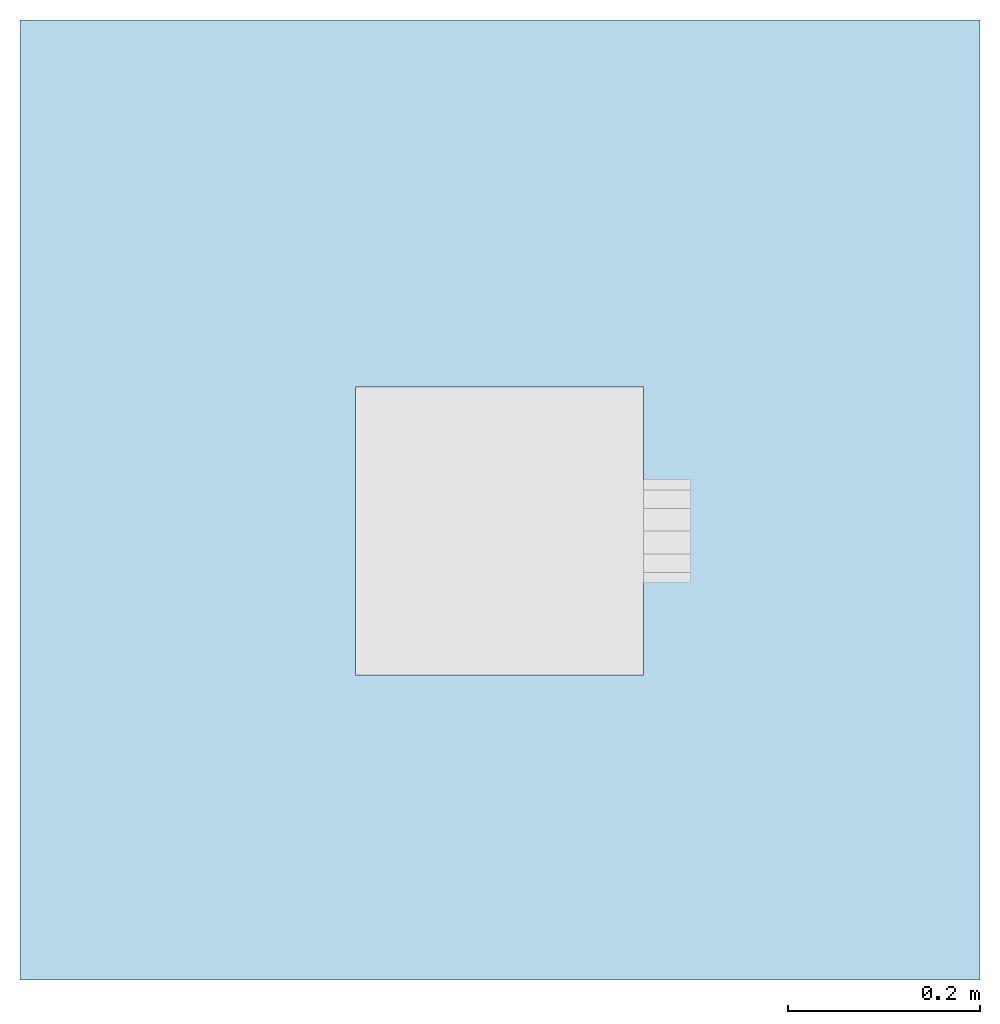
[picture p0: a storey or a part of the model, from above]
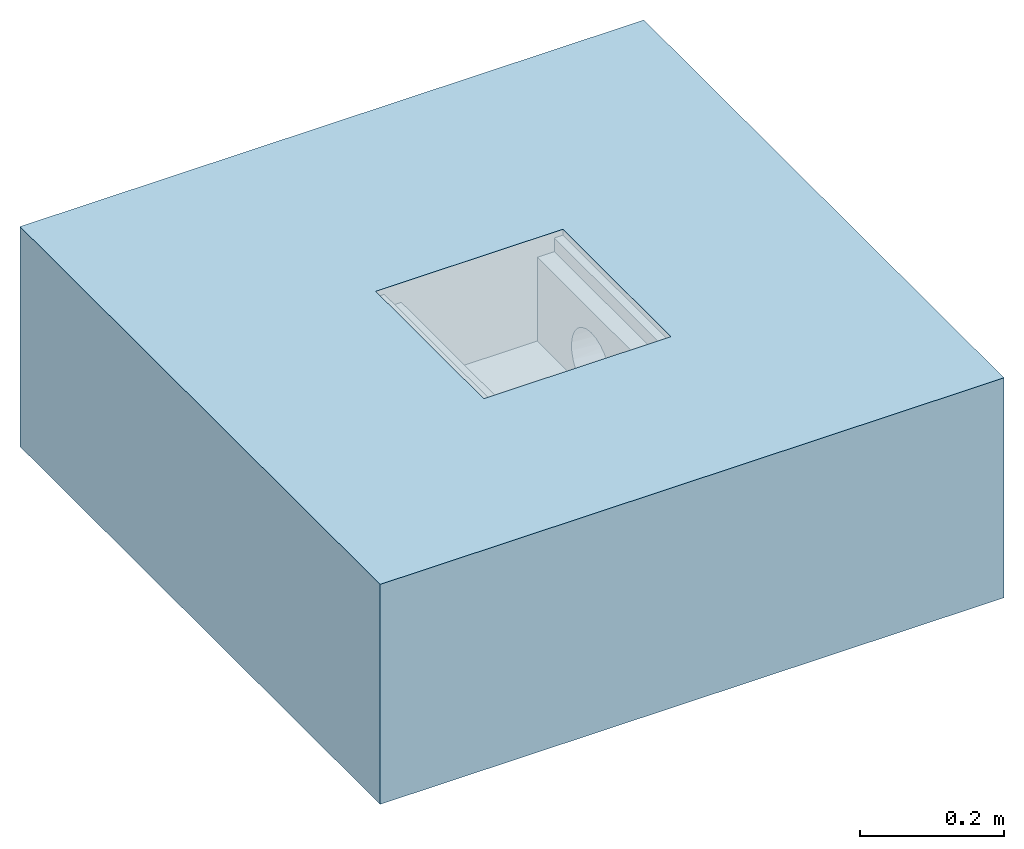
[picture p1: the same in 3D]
Properties of the parts of a building model (IFC2X3)

# File
Description: ViewDefinition [CoordinationView]
File name: Project Number
Time: 2014-10-30T17:54:26
Written by: The EXPRESS Data Manager Version 5.01.0100.02.64mod : 6 Jun 2012
Made in: 20130308_1515(x64) - Exporter 2014.0.2013.0308 - Default UI
Comment: STEP Physical File produced by: The EXPRESS Data Manager Version 5.01.0100.02.64mod : 6 Jun 2012 * Module: EDMstepFileFactory/EDMstandAlone * Creation date: Thu Oct 30 17:54:26 2014 * Host: IN-BLR-PC-0012 * Database: C:\Users\pponnur\AppData\Local\Temp\{3C13CAEE-00F8-4EB4-A701-3729015A9412}\ifc * Database version: 5507 * Database creation date: Thu Oct 30 17:54:22 2014 * Schema: IFC2X3 * Model: DataRepository.ifc * Model creation date: Thu Oct 30 17:54:23 2014 * Header model: DataRepository.ifc_HeaderModel * Header model creation date: Thu Oct 30 17:54:23 2014 * EDMuser: sdai-user * EDMgroup: sdai-group * License ID and type: 5605 : Permanent license. Expiry date: * EDMstepFileFactory options: 020000

# IfcProject, Project Number
LongName: Project Name; Phase: Project Status

# IfcSite, Default
RefLatitude: 42, 21, 30, 344238; RefLongitude: -71, -3, -35, -194702; RefElevation: 0 mm

# IfcBuilding
Pset_BuildingCommon - NumberOfStoreys: 1
Other - Project Number: Project Number; Project Issue Date: Issue Date; Project Name: Project Name; Project Status: Project Status; Client Name: Owner; Project Address: Enter address here

# IfcBuildingStorey, Level 1
LongName: Level 1; Elevation: 0 mm
Constraints - Elevation Base: Project Base Point; Elevation: 0 mm
Graphics - Line Pattern: Grid Line 1/2"; Symbol: Level Head - Circle: Level Head - Circle; Symbol at End 2 Default: yes; Color: 0; Line Weight: 1; Symbol at End 1 Default: no
Dimensions - Computation Height: 0 mm
Identity Data - Structural: no; Name: Level 1; Building Story: yes

# IfcFlowTerminal: 408013 - Fixed Height Gully - 300 x 300mm Top Size, ACO BD Gully 218 - Fixed Height - Horizontal Outlet:408013 - Fixed Height Gully - 300 x 300mm Top Size:187059
In: Level 1
Material: Stainless Steel AISI 304, Rubber, Nitrile
General - Price: POA - contact ACO; Product Standard: EN 1253; Foul Air Trap Seal Material: NBR; Gully Material: Stainless steel 1.4301 (EN 10088); Maintenance guidelines: http://issuu.com/acobuildingdrainage/docs/120820112708-138bdc871b784edfa2b6b8197acfd881?e=0; Product Type: Point Drainage; Installation guidelines: http://issuu.com/acobuildingdrainage/docs/120820112708-138bdc871b784edfa2b6b8197acfd881?e=0; Product Range: ACO gully 218; Foul Air Trap Seal Recycled Material Content: 0%; Outlet Diameter (mm): 110; Gully Recyclable: Fully recyclable; Gully top Grate size (mm): 300 x 300; NBS Specification: R11 ABOVE GROUND FOUL DRAINAGE SYSTEMS : Clause 315; Foul Air Trap Seal Colour: Black; Gully Colour: passivated stainless steel surface ( matt grey); Gully Recycled Material Content: 20 - 30 %; Gully Product Description: ACO gully 218 fixed height 300x300/DN 100 horizontal with foul air trap; Foul Air Trap Seal Recyclable: Fully recyclable; Gully Product Code: 408013; Load Class: A15 - C250 (EN 1253); Flow Rate (l/s): 4.4 l/s
Construction - 408042 - 268 x 268mm - Volcano Grating - Slip Resistant - Stainless Steel 304: no; 408041 - 268 x 268mm - Arla Grating - Slip Resistant - Stainless Steel 304: no; 408040 - 268 x 268mm - HeelSafe Grating - Brushed - Stainless Steel 304: no; 408038 - 268 x 268mm - Ladder Grating - Plain - Stainless Steel 304: no; 408036 - 268 x 268mm - Quadrato Grating - Brushed - Stainless steel 304: no; 408220 - Foul Air Trap & 408221 - Foul Air Trap Support Ring: yes; 408039 - 268 x 268mm - Slot Cover - Plain - Stainless Steel 304: no; 408045 - 268 x 268mm - Ladder Grating - Plain - Stainless Steel 304: no; 408037 - 268 x 268mm - Ladder Grating - Slip Resistant - Stainless steel 304: no; 408035 - 268 x 268mm - Mesh Grating - Plain - Stainless Steel 304: no; 408034 - 268 x 268mm - Mesh Grating - Slip Resistant - Stainless Steel 304: no; 408223 - Silt Basket: yes
Constraints - Level: Level: Level 1
Mechanical - System Classification: Sanitary
Phasing - Phase Created: New Construction
Identity Data - Mark: 1; Website: www.acobd.com www.acobd.com; Manufacturer: ACO Building Drainage; Water Marked With: BIM Manager Premium Suite; Telephone: +44 (0)1462 816666; E-mail Technical: abdtechnical@aco.co.uk; Address: ACO Business Centre, Caxton Road, Bedford, MK41 0LF; Water Mark 1: This file is the property of ACO Technologies PLC; Water Mark 2: This file is water marked and users are prohibited to reproduce, adapt, distribute this information; Fax: +44 (0)1462 851490; E-mail Sales: abdcommercial@aco.co.uk; Watermarked By: www.acobd.com www.acobd.com
Pset_ManufacturerTypeInformation - Manufacturer: ACO Building Drainage
Model Properties - Grating Product Code 408034: Load Class L15 (EN 1253) - Mesh Grating - Slip Resistant - Stainless steel 1.4301 (EN 10088) - 268 x 268 x 30mm; Grating Product Code 408035: Load Class L15 (EN 1253) - Mesh Grating - Plain - Stainless steel 1.4301 (EN 10088) - 268 x 268 x 30mm; Grating Product Code 408038: Load Class M125 (EN 1253) - Ladder Grating -Plain - Stainless steel 1.4301 (EN 10088) - 268 x 268 x 30mm; Grating Product Code 408045: Load Class C250 (EN 1253) - Ladder Grating - Plain - Stainless steel 1.4301 (EN 10088) - 268 x 268 x 30mm; Grating Product Code 408040: Load Class L15 (EN 1253) - Heelsafe Grating -Brushed- Stainless steel 1.4301 (EN 10088) - 268 x 268 x 30mm; Grating Product Code 408041: Load Class L15 (EN 1253) - Arla Grating - Slip Resistant - Stainless steel 1.4301 (EN 10088) - 268 x 268 x 30mm; Grating Product Code 408037: Load Class M125 (EN 1253) - Ladder Grating -Slip Resistant - Stainless steel 1.4301 (EN 10088) - 268 x 268 x 30mm; Product Code 408223: Silt Basket - Stainless Steel 304; Product Code 408221: Foul Air Trap Support Ring - Nitrile; Grating Product Code 408042: Load Class M125 (EN 1253) - Volcano Grating - Slip Resistant - Stainless steel 1.4301 (EN 10088) - 268 x 268 x 30mm; Grating Product Code 408039: Load Class M125 (EN 1253) - Slot Cover - Plain - Stainless steel 1.4301 (EN 10088) - 268 x 268 x 30mm; Product Code 408220: Foul Air Trap - Stainless Steel 304; Grating Product Code 408036: Load Class L15 (EN 1253) - Quadrato Grating - Brushed - Stainless steel 1.4301 (EN 10088) - 268 x 268 x 30mm

# IfcOpeningElement: Recess
In: Level 1
Dimensions - Area: 10.7639 ft2; Perimeter: 4000 mm; Thickness: 372.8 mm; Volume: 12.7089 ft3
Constraints - Height Offset From Level: 0 mm; Level: Level: Level 1; Room Bounding: yes; Related to Mass: no
Phasing - Phase Created: New Construction
Structural - Structural: no; Enable Analytical Model: no
Identity Data - Assembly Code: B1010; Assembly Description: Floor Construction
Analytical Properties - Absorptance: 0.7; Thermal mass: 53301.1; Heat Transfer Coefficient (U): 1.55882; Roughness: 3; Thermal Resistance (R): 0.641509
Graphics - Coarse Scale Fill Color: 0
Construction - Function: Interior; Default Thickness: 372.8 mm

# IfcSlab: Floor:Generic - 12", Floor:Generic - 12":184145
In: Level 1
PredefinedType: FLOOR; Material: Plywood, Sheathing 68 mm, Default Floor 304.8 mm
Dimensions - Area: 10.7639 ft2; Perimeter: 4000 mm; Thickness: 372.8 mm; Volume: 12.7089 ft3
Constraints - Height Offset From Level: 0 mm; Level: Level: Level 1; Room Bounding: yes; Related to Mass: no
Phasing - Phase Created: New Construction
Structural - Structural: no; Enable Analytical Model: no
Pset_SlabCommon - Reference: Generic - 12"; IsExternal: no; LoadBearing: yes; ThermalTransmittance: 1.55882 kg/K/s3
Identity Data - Assembly Code: B1010; Assembly Description: Floor Construction
Analytical Properties - Absorptance: 0.7; Thermal mass: 53301.1; Heat Transfer Coefficient (U): 1.55882; Roughness: 3; Thermal Resistance (R): 0.641509
Graphics - Coarse Scale Fill Color: 0
Construction - Function: Interior; Default Thickness: 372.8 mm
